VERSION 5.7 ;
BUSBITCHARS "[]" ;
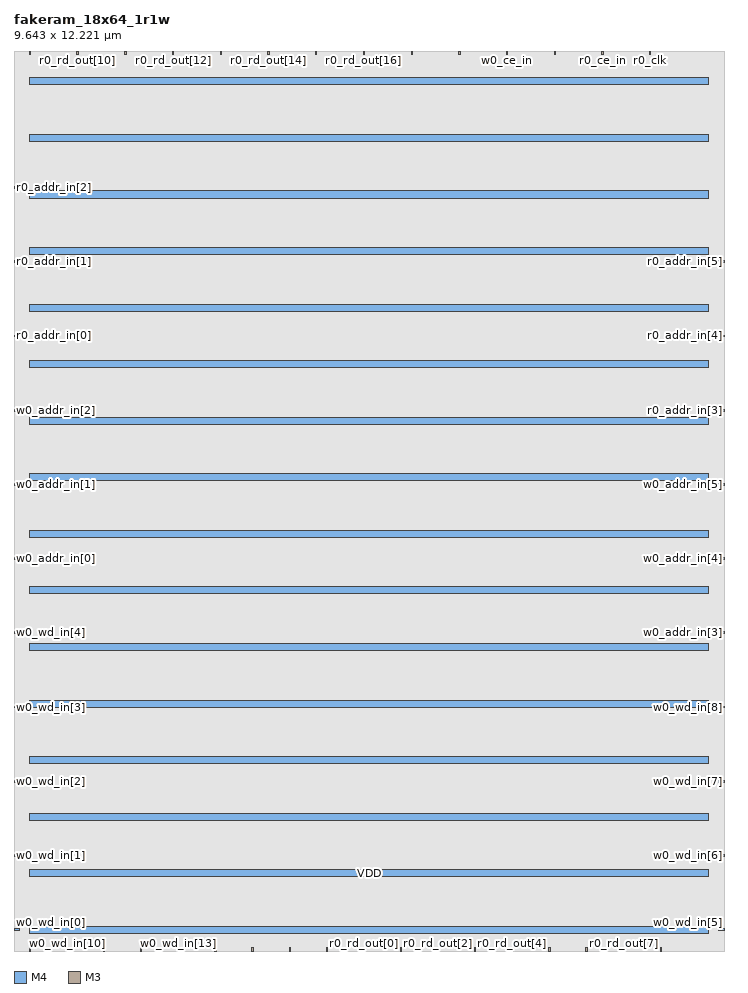
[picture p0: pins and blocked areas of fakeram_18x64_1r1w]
MACRO fakeram_18x64_1r1w
  FOREIGN fakeram_18x64_1r1w 0 0 ;
  SYMMETRY X Y R90 ;
  SIZE 9.643 BY 12.221 ;
  CLASS BLOCK ;
  PIN w0_wd_in[0]
    DIRECTION INPUT ;
    USE SIGNAL ;
    SHAPE ABUTMENT ;
    PORT
      LAYER M4 ;
      RECT 0.000 0.276 0.072 0.300 ;
    END
  END w0_wd_in[0]
  PIN w0_wd_in[1]
    DIRECTION INPUT ;
    USE SIGNAL ;
    SHAPE ABUTMENT ;
    PORT
      LAYER M4 ;
      RECT 0.000 1.284 0.072 1.308 ;
    END
  END w0_wd_in[1]
  PIN w0_wd_in[2]
    DIRECTION INPUT ;
    USE SIGNAL ;
    SHAPE ABUTMENT ;
    PORT
      LAYER M4 ;
      RECT 0.000 2.292 0.072 2.316 ;
    END
  END w0_wd_in[2]
  PIN w0_wd_in[3]
    DIRECTION INPUT ;
    USE SIGNAL ;
    SHAPE ABUTMENT ;
    PORT
      LAYER M4 ;
      RECT 0.000 3.300 0.072 3.324 ;
    END
  END w0_wd_in[3]
  PIN w0_wd_in[4]
    DIRECTION INPUT ;
    USE SIGNAL ;
    SHAPE ABUTMENT ;
    PORT
      LAYER M4 ;
      RECT 0.000 4.308 0.072 4.332 ;
    END
  END w0_wd_in[4]
  PIN w0_wd_in[5]
    DIRECTION INPUT ;
    USE SIGNAL ;
    SHAPE ABUTMENT ;
    PORT
      LAYER M4 ;
      RECT 9.571 0.276 9.643 0.300 ;
    END
  END w0_wd_in[5]
  PIN w0_wd_in[6]
    DIRECTION INPUT ;
    USE SIGNAL ;
    SHAPE ABUTMENT ;
    PORT
      LAYER M4 ;
      RECT 9.571 1.284 9.643 1.308 ;
    END
  END w0_wd_in[6]
  PIN w0_wd_in[7]
    DIRECTION INPUT ;
    USE SIGNAL ;
    SHAPE ABUTMENT ;
    PORT
      LAYER M4 ;
      RECT 9.571 2.292 9.643 2.316 ;
    END
  END w0_wd_in[7]
  PIN w0_wd_in[8]
    DIRECTION INPUT ;
    USE SIGNAL ;
    SHAPE ABUTMENT ;
    PORT
      LAYER M4 ;
      RECT 9.571 3.300 9.643 3.324 ;
    END
  END w0_wd_in[8]
  PIN w0_wd_in[9]
    DIRECTION OUTPUT ;
    USE SIGNAL ;
    SHAPE ABUTMENT ;
    PORT
      LAYER M3 ;
      RECT 0.207 0.000 0.225 0.054 ;
    END
  END w0_wd_in[9]
  PIN w0_wd_in[10]
    DIRECTION OUTPUT ;
    USE SIGNAL ;
    SHAPE ABUTMENT ;
    PORT
      LAYER M3 ;
      RECT 0.711 0.000 0.729 0.054 ;
    END
  END w0_wd_in[10]
  PIN w0_wd_in[11]
    DIRECTION OUTPUT ;
    USE SIGNAL ;
    SHAPE ABUTMENT ;
    PORT
      LAYER M3 ;
      RECT 1.215 0.000 1.233 0.054 ;
    END
  END w0_wd_in[11]
  PIN w0_wd_in[12]
    DIRECTION OUTPUT ;
    USE SIGNAL ;
    SHAPE ABUTMENT ;
    PORT
      LAYER M3 ;
      RECT 1.719 0.000 1.737 0.054 ;
    END
  END w0_wd_in[12]
  PIN w0_wd_in[13]
    DIRECTION OUTPUT ;
    USE SIGNAL ;
    SHAPE ABUTMENT ;
    PORT
      LAYER M3 ;
      RECT 2.223 0.000 2.241 0.054 ;
    END
  END w0_wd_in[13]
  PIN w0_wd_in[14]
    DIRECTION OUTPUT ;
    USE SIGNAL ;
    SHAPE ABUTMENT ;
    PORT
      LAYER M3 ;
      RECT 2.727 0.000 2.745 0.054 ;
    END
  END w0_wd_in[14]
  PIN w0_wd_in[15]
    DIRECTION OUTPUT ;
    USE SIGNAL ;
    SHAPE ABUTMENT ;
    PORT
      LAYER M3 ;
      RECT 3.231 0.000 3.249 0.054 ;
    END
  END w0_wd_in[15]
  PIN w0_wd_in[16]
    DIRECTION OUTPUT ;
    USE SIGNAL ;
    SHAPE ABUTMENT ;
    PORT
      LAYER M3 ;
      RECT 3.735 0.000 3.753 0.054 ;
    END
  END w0_wd_in[16]
  PIN w0_wd_in[17]
    DIRECTION OUTPUT ;
    USE SIGNAL ;
    SHAPE ABUTMENT ;
    PORT
      LAYER M3 ;
      RECT 4.239 0.000 4.257 0.054 ;
    END
  END w0_wd_in[17]
  PIN r0_rd_out[0]
    DIRECTION OUTPUT ;
    USE SIGNAL ;
    SHAPE ABUTMENT ;
    PORT
      LAYER M3 ;
      RECT 4.743 0.000 4.761 0.054 ;
    END
  END r0_rd_out[0]
  PIN r0_rd_out[1]
    DIRECTION OUTPUT ;
    USE SIGNAL ;
    SHAPE ABUTMENT ;
    PORT
      LAYER M3 ;
      RECT 5.247 0.000 5.265 0.054 ;
    END
  END r0_rd_out[1]
  PIN r0_rd_out[2]
    DIRECTION OUTPUT ;
    USE SIGNAL ;
    SHAPE ABUTMENT ;
    PORT
      LAYER M3 ;
      RECT 5.751 0.000 5.769 0.054 ;
    END
  END r0_rd_out[2]
  PIN r0_rd_out[3]
    DIRECTION OUTPUT ;
    USE SIGNAL ;
    SHAPE ABUTMENT ;
    PORT
      LAYER M3 ;
      RECT 6.255 0.000 6.273 0.054 ;
    END
  END r0_rd_out[3]
  PIN r0_rd_out[4]
    DIRECTION OUTPUT ;
    USE SIGNAL ;
    SHAPE ABUTMENT ;
    PORT
      LAYER M3 ;
      RECT 6.759 0.000 6.777 0.054 ;
    END
  END r0_rd_out[4]
  PIN r0_rd_out[5]
    DIRECTION OUTPUT ;
    USE SIGNAL ;
    SHAPE ABUTMENT ;
    PORT
      LAYER M3 ;
      RECT 7.263 0.000 7.281 0.054 ;
    END
  END r0_rd_out[5]
  PIN r0_rd_out[6]
    DIRECTION OUTPUT ;
    USE SIGNAL ;
    SHAPE ABUTMENT ;
    PORT
      LAYER M3 ;
      RECT 7.767 0.000 7.785 0.054 ;
    END
  END r0_rd_out[6]
  PIN r0_rd_out[7]
    DIRECTION OUTPUT ;
    USE SIGNAL ;
    SHAPE ABUTMENT ;
    PORT
      LAYER M3 ;
      RECT 8.271 0.000 8.289 0.054 ;
    END
  END r0_rd_out[7]
  PIN r0_rd_out[8]
    DIRECTION OUTPUT ;
    USE SIGNAL ;
    SHAPE ABUTMENT ;
    PORT
      LAYER M3 ;
      RECT 8.775 0.000 8.793 0.054 ;
    END
  END r0_rd_out[8]
  PIN r0_rd_out[9]
    DIRECTION OUTPUT ;
    USE SIGNAL ;
    SHAPE ABUTMENT ;
    PORT
      LAYER M3 ;
      RECT 0.207 12.167 0.225 12.221 ;
    END
  END r0_rd_out[9]
  PIN r0_rd_out[10]
    DIRECTION OUTPUT ;
    USE SIGNAL ;
    SHAPE ABUTMENT ;
    PORT
      LAYER M3 ;
      RECT 0.855 12.167 0.873 12.221 ;
    END
  END r0_rd_out[10]
  PIN r0_rd_out[11]
    DIRECTION OUTPUT ;
    USE SIGNAL ;
    SHAPE ABUTMENT ;
    PORT
      LAYER M3 ;
      RECT 1.503 12.167 1.521 12.221 ;
    END
  END r0_rd_out[11]
  PIN r0_rd_out[12]
    DIRECTION OUTPUT ;
    USE SIGNAL ;
    SHAPE ABUTMENT ;
    PORT
      LAYER M3 ;
      RECT 2.151 12.167 2.169 12.221 ;
    END
  END r0_rd_out[12]
  PIN r0_rd_out[13]
    DIRECTION OUTPUT ;
    USE SIGNAL ;
    SHAPE ABUTMENT ;
    PORT
      LAYER M3 ;
      RECT 2.799 12.167 2.817 12.221 ;
    END
  END r0_rd_out[13]
  PIN r0_rd_out[14]
    DIRECTION OUTPUT ;
    USE SIGNAL ;
    SHAPE ABUTMENT ;
    PORT
      LAYER M3 ;
      RECT 3.447 12.167 3.465 12.221 ;
    END
  END r0_rd_out[14]
  PIN r0_rd_out[15]
    DIRECTION OUTPUT ;
    USE SIGNAL ;
    SHAPE ABUTMENT ;
    PORT
      LAYER M3 ;
      RECT 4.095 12.167 4.113 12.221 ;
    END
  END r0_rd_out[15]
  PIN r0_rd_out[16]
    DIRECTION OUTPUT ;
    USE SIGNAL ;
    SHAPE ABUTMENT ;
    PORT
      LAYER M3 ;
      RECT 4.743 12.167 4.761 12.221 ;
    END
  END r0_rd_out[16]
  PIN r0_rd_out[17]
    DIRECTION OUTPUT ;
    USE SIGNAL ;
    SHAPE ABUTMENT ;
    PORT
      LAYER M3 ;
      RECT 5.391 12.167 5.409 12.221 ;
    END
  END r0_rd_out[17]
  PIN w0_addr_in[0]
    DIRECTION INPUT ;
    USE SIGNAL ;
    SHAPE ABUTMENT ;
    PORT
      LAYER M4 ;
      RECT 0.000 5.316 0.072 5.340 ;
    END
  END w0_addr_in[0]
  PIN w0_addr_in[1]
    DIRECTION INPUT ;
    USE SIGNAL ;
    SHAPE ABUTMENT ;
    PORT
      LAYER M4 ;
      RECT 0.000 6.324 0.072 6.348 ;
    END
  END w0_addr_in[1]
  PIN w0_addr_in[2]
    DIRECTION INPUT ;
    USE SIGNAL ;
    SHAPE ABUTMENT ;
    PORT
      LAYER M4 ;
      RECT 0.000 7.332 0.072 7.356 ;
    END
  END w0_addr_in[2]
  PIN w0_addr_in[3]
    DIRECTION INPUT ;
    USE SIGNAL ;
    SHAPE ABUTMENT ;
    PORT
      LAYER M4 ;
      RECT 9.571 4.308 9.643 4.332 ;
    END
  END w0_addr_in[3]
  PIN w0_addr_in[4]
    DIRECTION INPUT ;
    USE SIGNAL ;
    SHAPE ABUTMENT ;
    PORT
      LAYER M4 ;
      RECT 9.571 5.316 9.643 5.340 ;
    END
  END w0_addr_in[4]
  PIN w0_addr_in[5]
    DIRECTION INPUT ;
    USE SIGNAL ;
    SHAPE ABUTMENT ;
    PORT
      LAYER M4 ;
      RECT 9.571 6.324 9.643 6.348 ;
    END
  END w0_addr_in[5]
  PIN r0_addr_in[0]
    DIRECTION INPUT ;
    USE SIGNAL ;
    SHAPE ABUTMENT ;
    PORT
      LAYER M4 ;
      RECT 0.000 8.340 0.072 8.364 ;
    END
  END r0_addr_in[0]
  PIN r0_addr_in[1]
    DIRECTION INPUT ;
    USE SIGNAL ;
    SHAPE ABUTMENT ;
    PORT
      LAYER M4 ;
      RECT 0.000 9.348 0.072 9.372 ;
    END
  END r0_addr_in[1]
  PIN r0_addr_in[2]
    DIRECTION INPUT ;
    USE SIGNAL ;
    SHAPE ABUTMENT ;
    PORT
      LAYER M4 ;
      RECT 0.000 10.356 0.072 10.380 ;
    END
  END r0_addr_in[2]
  PIN r0_addr_in[3]
    DIRECTION INPUT ;
    USE SIGNAL ;
    SHAPE ABUTMENT ;
    PORT
      LAYER M4 ;
      RECT 9.571 7.332 9.643 7.356 ;
    END
  END r0_addr_in[3]
  PIN r0_addr_in[4]
    DIRECTION INPUT ;
    USE SIGNAL ;
    SHAPE ABUTMENT ;
    PORT
      LAYER M4 ;
      RECT 9.571 8.340 9.643 8.364 ;
    END
  END r0_addr_in[4]
  PIN r0_addr_in[5]
    DIRECTION INPUT ;
    USE SIGNAL ;
    SHAPE ABUTMENT ;
    PORT
      LAYER M4 ;
      RECT 9.571 9.348 9.643 9.372 ;
    END
  END r0_addr_in[5]
  PIN w0_we_in
    DIRECTION INPUT ;
    USE SIGNAL ;
    SHAPE ABUTMENT ;
    PORT
      LAYER M3 ;
      RECT 6.039 12.167 6.057 12.221 ;
    END
  END w0_we_in
  PIN w0_ce_in
    DIRECTION INPUT ;
    USE SIGNAL ;
    SHAPE ABUTMENT ;
    PORT
      LAYER M3 ;
      RECT 6.687 12.167 6.705 12.221 ;
    END
  END w0_ce_in
  PIN w0_clk
    DIRECTION INPUT ;
    USE SIGNAL ;
    SHAPE ABUTMENT ;
    PORT
      LAYER M3 ;
      RECT 7.335 12.167 7.353 12.221 ;
    END
  END w0_clk
  PIN r0_ce_in
    DIRECTION INPUT ;
    USE SIGNAL ;
    SHAPE ABUTMENT ;
    PORT
      LAYER M3 ;
      RECT 7.983 12.167 8.001 12.221 ;
    END
  END r0_ce_in
  PIN r0_clk
    DIRECTION INPUT ;
    USE SIGNAL ;
    SHAPE ABUTMENT ;
    PORT
      LAYER M3 ;
      RECT 8.631 12.167 8.649 12.221 ;
    END
  END r0_clk
  PIN VSS
    DIRECTION INOUT ;
    USE GROUND ;
    PORT
      LAYER M4 ;
      RECT 0.216 0.240 9.427 0.336 ;
      RECT 0.216 1.008 9.427 1.104 ;
      RECT 0.216 1.776 9.427 1.872 ;
      RECT 0.216 2.544 9.427 2.640 ;
      RECT 0.216 3.312 9.427 3.408 ;
      RECT 0.216 4.080 9.427 4.176 ;
      RECT 0.216 4.848 9.427 4.944 ;
      RECT 0.216 5.616 9.427 5.712 ;
      RECT 0.216 6.384 9.427 6.480 ;
      RECT 0.216 7.152 9.427 7.248 ;
      RECT 0.216 7.920 9.427 8.016 ;
      RECT 0.216 8.688 9.427 8.784 ;
      RECT 0.216 9.456 9.427 9.552 ;
      RECT 0.216 10.224 9.427 10.320 ;
      RECT 0.216 10.992 9.427 11.088 ;
      RECT 0.216 11.760 9.427 11.856 ;
    END
  END VSS
  PIN VDD
    DIRECTION INOUT ;
    USE POWER ;
    PORT
      LAYER M4 ;
      RECT 0.216 0.240 9.427 0.336 ;
      RECT 0.216 1.008 9.427 1.104 ;
      RECT 0.216 1.776 9.427 1.872 ;
      RECT 0.216 2.544 9.427 2.640 ;
      RECT 0.216 3.312 9.427 3.408 ;
      RECT 0.216 4.080 9.427 4.176 ;
      RECT 0.216 4.848 9.427 4.944 ;
      RECT 0.216 5.616 9.427 5.712 ;
      RECT 0.216 6.384 9.427 6.480 ;
      RECT 0.216 7.152 9.427 7.248 ;
      RECT 0.216 7.920 9.427 8.016 ;
      RECT 0.216 8.688 9.427 8.784 ;
      RECT 0.216 9.456 9.427 9.552 ;
      RECT 0.216 10.224 9.427 10.320 ;
      RECT 0.216 10.992 9.427 11.088 ;
      RECT 0.216 11.760 9.427 11.856 ;
    END
  END VDD
  OBS
    LAYER M1 ;
    RECT 0 0 9.643 12.221 ;
    LAYER M2 ;
    RECT 0 0 9.643 12.221 ;
    LAYER M3 ;
    RECT 0 0 9.643 12.221 ;
    LAYER M4 ;
    RECT 0 0 9.643 12.221 ;
  END
END fakeram_18x64_1r1w

END LIBRARY
